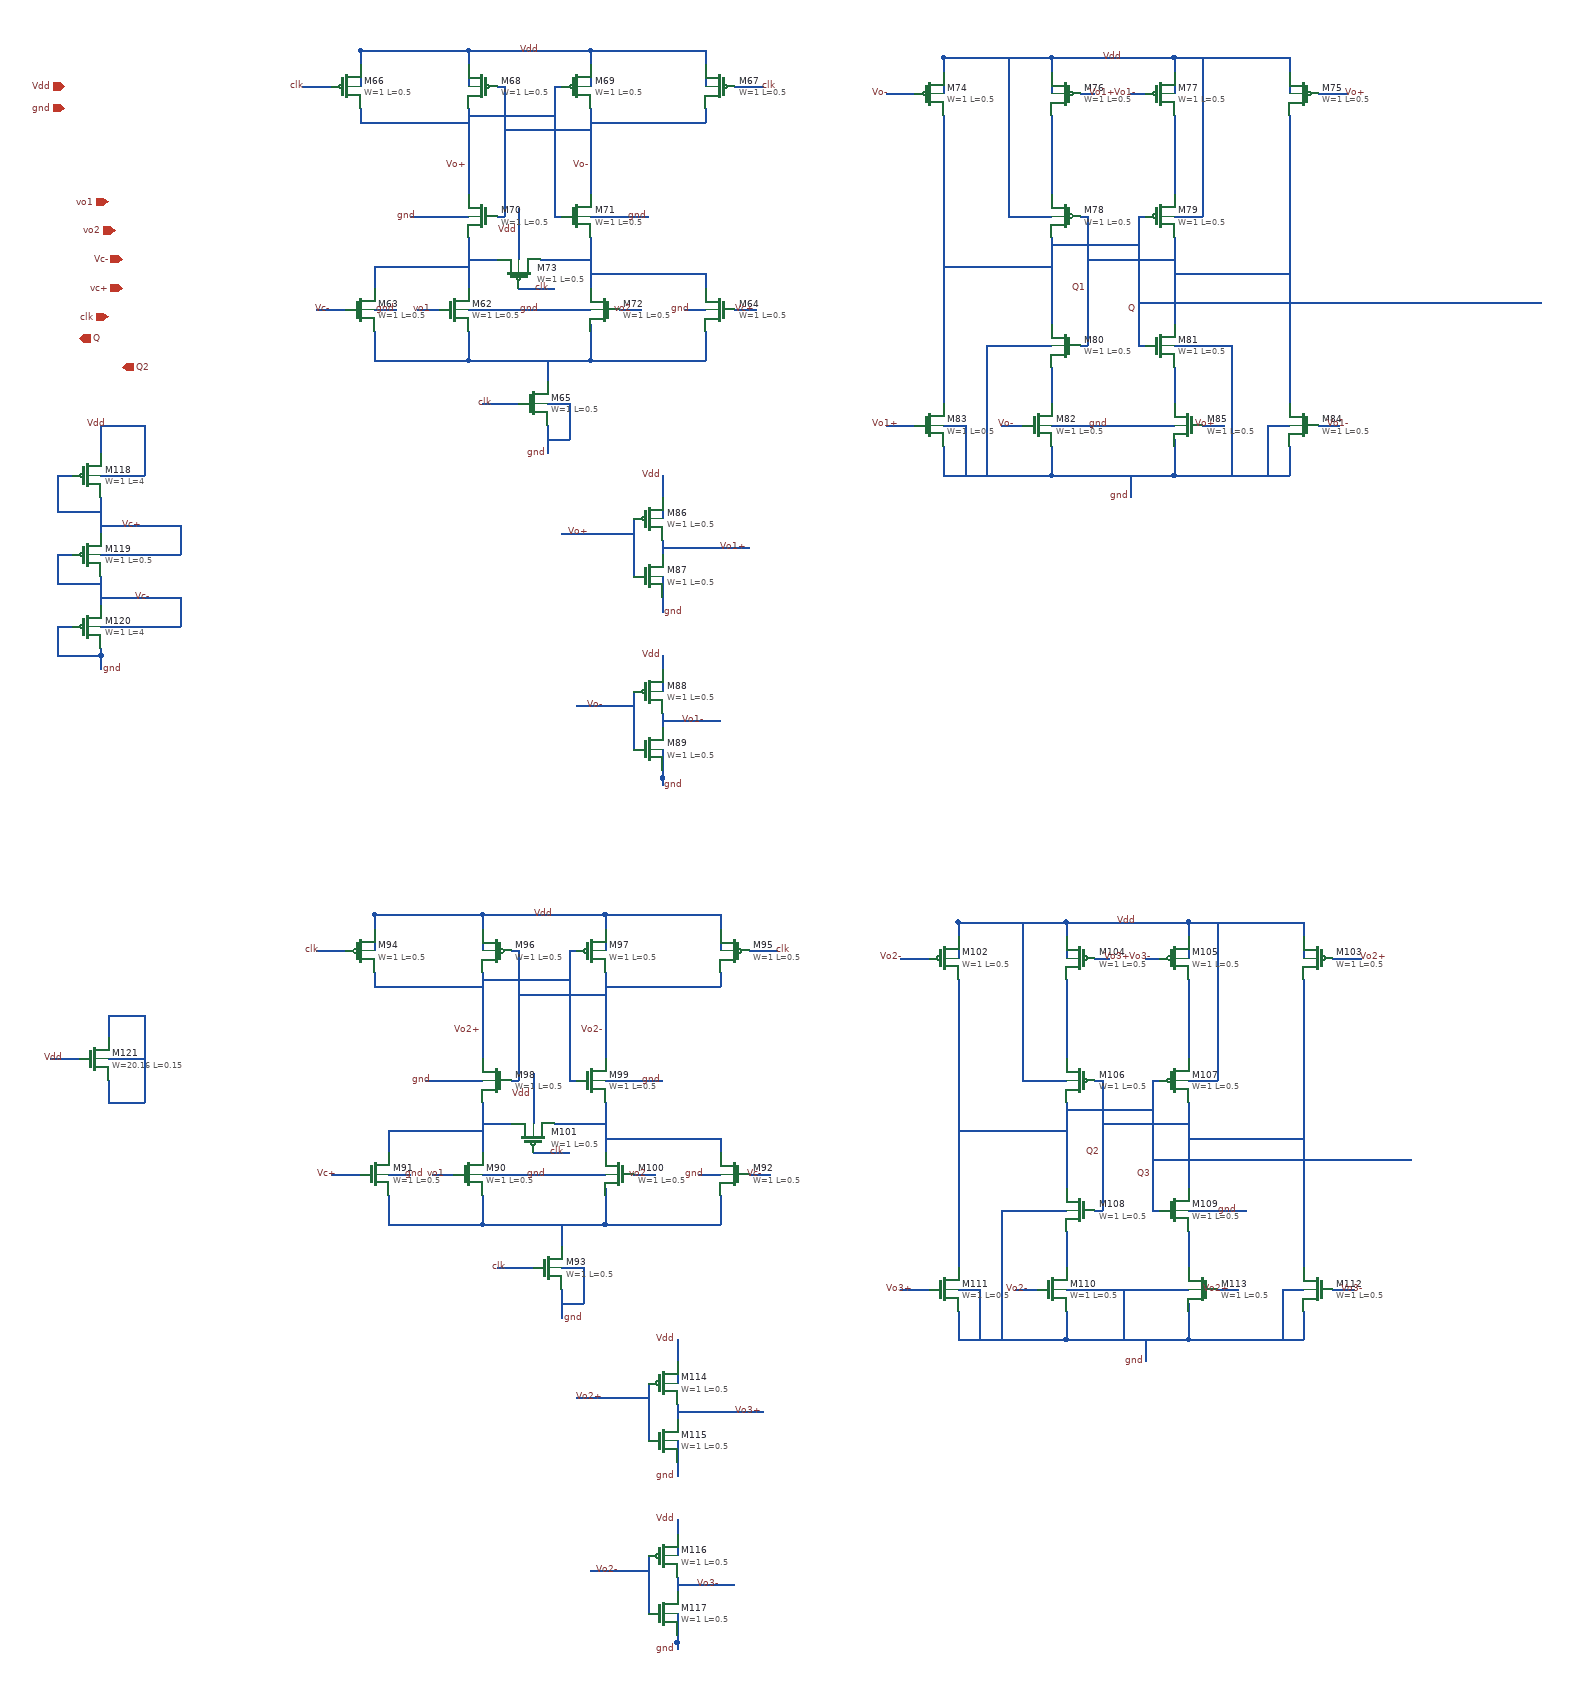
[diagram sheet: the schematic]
v {xschem version=3.4.4 file_version=1.2
}
G {}
K {}
V {}
S {}
E {}
N -830 -240 -830 -120 {
lab=Vo+}
N -660 -240 -660 -130 {
lab=Vo-}
N -660 -130 -660 -120 {
lab=Vo-}
N -830 -320 -830 -300 {
lab=Vdd}
N -830 -320 -660 -320 {
lab=Vdd}
N -660 -320 -660 -300 {
lab=Vdd}
N -790 -270 -780 -270 {
lab=Vo-}
N -780 -270 -780 -90 {
lab=Vo-}
N -790 -90 -780 -90 {
lab=Vo-}
N -710 -270 -700 -270 {
lab=Vo+}
N -710 -270 -710 -90 {
lab=Vo+}
N -710 -90 -700 -90 {
lab=Vo+}
N -980 -320 -830 -320 {
lab=Vdd}
N -980 -320 -980 -300 {
lab=Vdd}
N -660 -320 -500 -320 {
lab=Vdd}
N -500 -320 -500 -300 {
lab=Vdd}
N -980 -240 -980 -220 {
lab=Vo+}
N -980 -220 -830 -220 {
lab=Vo+}
N -500 -240 -500 -220 {
lab=Vo-}
N -660 -220 -500 -220 {
lab=Vo-}
N -830 -230 -710 -230 {
lab=Vo+}
N -780 -210 -660 -210 {
lab=Vo-}
N -830 -60 -830 10 {
lab=#net1}
N -660 -60 -660 10 {
lab=#net2}
N -830 70 -830 110 {
lab=#net3}
N -830 110 -660 110 {
lab=#net3}
N -660 60 -660 110 {
lab=#net3}
N -500 70 -500 110 {
lab=#net3}
N -660 110 -500 110 {
lab=#net3}
N -500 -10 -500 10 {
lab=#net2}
N -660 -10 -500 -10 {
lab=#net2}
N -960 70 -960 110 {
lab=#net3}
N -960 110 -830 110 {
lab=#net3}
N -960 -20 -960 10 {
lab=#net1}
N -960 -20 -830 -20 {
lab=#net1}
N -720 110 -720 140 {
lab=#net3}
N -810 170 -760 170 {
lab=clk}
N -720 200 -720 240 {
lab=gnd}
N -830 -30 -790 -30 {
lab=#net1}
N -730 -30 -660 -30 {
lab=#net2}
N -1040 40 -1000 40 {
lab=Vc-}
N -900 40 -870 40 {
lab=vo1}
N -620 40 -590 40 {
lab=vo2}
N -460 40 -430 40 {
lab=Vc+}
N -460 -270 -420 -270 {
lab=clk}
N -1060 -270 -1020 -270 {
lab=clk}
N -830 40 -660 40 {
lab=gnd}
N -530 40 -500 40 {
lab=gnd}
N -960 40 -930 40 {
lab=gnd}
N -980 -290 -980 -270 {
lab=Vdd}
N -830 -290 -830 -270 {
lab=Vdd}
N -660 -300 -660 -280 {
lab=Vdd}
N -660 -290 -660 -270 {
lab=Vdd}
N -500 -310 -500 -270 {
lab=Vdd}
N -830 -310 -830 -270 {
lab=Vdd}
N -980 -320 -980 -270 {
lab=Vdd}
N -660 -90 -580 -90 {
lab=gnd}
N -910 -90 -830 -90 {
lab=gnd}
N -760 -100 -760 -30 {
lab=Vdd}
N -760 10 -710 10 {
lab=clk}
N -720 170 -690 170 {
lab=gnd}
N -690 170 -690 220 {
lab=gnd}
N -720 220 -690 220 {
lab=gnd}
N -20 -310 -20 -290 {
lab=Vdd}
N -20 -310 150 -310 {
lab=Vdd}
N 150 -310 150 -290 {
lab=Vdd}
N 20 -260 30 -260 {
lab=Vo1+}
N 100 -260 110 -260 {
lab=Vo1-}
N -170 -310 -20 -310 {
lab=Vdd}
N -170 -310 -170 -290 {
lab=Vdd}
N 150 -310 310 -310 {
lab=Vdd}
N 310 -310 310 -290 {
lab=Vdd}
N -170 -230 -170 -210 {
lab=Q}
N 310 -230 310 -210 {
lab=Q1}
N 350 -260 390 -260 {
lab=Vo+}
N -250 -260 -210 -260 {
lab=Vo-}
N -170 -280 -170 -260 {
lab=Vdd}
N -20 -280 -20 -260 {
lab=Vdd}
N 150 -290 150 -270 {
lab=Vdd}
N 150 -280 150 -260 {
lab=Vdd}
N 310 -300 310 -260 {
lab=Vdd}
N -20 -300 -20 -260 {
lab=Vdd}
N -170 -310 -170 -260 {
lab=Vdd}
N 150 -230 150 -140 {
lab=#net4}
N -20 -60 -20 60 {
lab=Q}
N 150 -60 150 50 {
lab=Q1}
N 150 50 150 60 {
lab=Q1}
N -20 -140 -20 -120 {
lab=#net5}
N 150 -140 150 -120 {
lab=#net4}
N 20 -90 30 -90 {
lab=Q1}
N 30 -90 30 90 {
lab=Q1}
N 20 90 30 90 {
lab=Q1}
N 100 -90 110 -90 {
lab=Q}
N 100 -90 100 90 {
lab=Q}
N 100 90 110 90 {
lab=Q}
N -20 -50 100 -50 {
lab=Q}
N 30 -30 150 -30 {
lab=Q1}
N 150 90 230 90 {
lab=gnd}
N -20 -230 -20 -140 {
lab=#net5}
N -20 230 -20 270 {
lab=gnd}
N -20 270 150 270 {
lab=gnd}
N 150 220 150 270 {
lab=gnd}
N 310 230 310 270 {
lab=gnd}
N 150 270 310 270 {
lab=gnd}
N 310 150 310 170 {
lab=Q1}
N -170 230 -170 270 {
lab=gnd}
N -150 270 -20 270 {
lab=gnd}
N -170 140 -170 170 {
lab=Q}
N 90 270 90 300 {
lab=gnd}
N -250 200 -210 200 {
lab=Vo1+}
N -90 200 -60 200 {
lab=Vo-}
N 190 200 220 200 {
lab=Vo+}
N 350 200 380 200 {
lab=Vo1-}
N -20 200 150 200 {
lab=gnd}
N 280 200 310 200 {
lab=gnd}
N -170 200 -140 200 {
lab=gnd}
N -20 120 -20 170 {
lab=#net6}
N 150 120 150 170 {
lab=#net7}
N -170 -210 -170 140 {
lab=Q}
N 310 -210 310 140 {
lab=Q1}
N 310 140 310 150 {
lab=Q1}
N -170 270 -150 270 {
lab=gnd}
N 90 -260 100 -260 {
lab=Vo1-}
N 30 -260 40 -260 {
lab=Vo1+}
N -170 -20 -20 -20 {
lab=Q}
N 150 -10 310 -10 {
lab=Q1}
N -700 350 -620 350 {
lab=Vo+}
N -680 590 -600 590 {
lab=Vo-}
N -560 610 -480 610 {
lab=Vo1-}
N -80 -90 -20 -90 {
lab=Vdd}
N -80 -310 -80 -90 {
lab=Vdd}
N 150 -90 190 -90 {
lab=Vdd}
N 190 -310 190 -90 {
lab=Vdd}
N -110 90 -20 90 {
lab=gnd}
N -110 90 -110 270 {
lab=gnd}
N -560 440 -560 460 {
lab=gnd}
N -600 330 -600 410 {
lab=Vo+}
N -620 350 -600 350 {
lab=Vo+}
N -560 360 -560 380 {
lab=Vo1+}
N -560 370 -440 370 {
lab=Vo1+}
N -560 270 -560 300 {
lab=Vdd}
N -560 280 -560 330 {
lab=Vdd}
N -560 410 -560 450 {
lab=gnd}
N -600 570 -600 650 {
lab=Vo-}
N -560 600 -560 620 {
lab=Vo1-}
N -560 690 -560 700 {
lab=gnd}
N -560 680 -560 690 {
lab=gnd}
N -560 650 -560 690 {
lab=gnd}
N -560 520 -560 540 {
lab=Vdd}
N -560 530 -560 570 {
lab=Vdd}
N -810 960 -810 1080 {
lab=Vo2+}
N -640 960 -640 1070 {
lab=Vo2-}
N -640 1070 -640 1080 {
lab=Vo2-}
N -810 880 -810 900 {
lab=Vdd}
N -810 880 -640 880 {
lab=Vdd}
N -640 880 -640 900 {
lab=Vdd}
N -770 930 -760 930 {
lab=Vo2-}
N -760 930 -760 1110 {
lab=Vo2-}
N -770 1110 -760 1110 {
lab=Vo2-}
N -690 930 -680 930 {
lab=Vo2+}
N -690 930 -690 1110 {
lab=Vo2+}
N -690 1110 -680 1110 {
lab=Vo2+}
N -960 880 -810 880 {
lab=Vdd}
N -960 880 -960 900 {
lab=Vdd}
N -640 880 -480 880 {
lab=Vdd}
N -480 880 -480 900 {
lab=Vdd}
N -960 960 -960 980 {
lab=Vo2+}
N -960 980 -810 980 {
lab=Vo2+}
N -480 960 -480 980 {
lab=Vo2-}
N -640 980 -480 980 {
lab=Vo2-}
N -810 970 -690 970 {
lab=Vo2+}
N -760 990 -640 990 {
lab=Vo2-}
N -810 1140 -810 1210 {
lab=#net8}
N -640 1140 -640 1210 {
lab=#net9}
N -810 1270 -810 1310 {
lab=#net10}
N -810 1310 -640 1310 {
lab=#net10}
N -640 1260 -640 1310 {
lab=#net10}
N -480 1270 -480 1310 {
lab=#net10}
N -640 1310 -480 1310 {
lab=#net10}
N -480 1190 -480 1210 {
lab=#net9}
N -640 1190 -480 1190 {
lab=#net9}
N -940 1270 -940 1310 {
lab=#net10}
N -940 1310 -810 1310 {
lab=#net10}
N -940 1180 -940 1210 {
lab=#net8}
N -940 1180 -810 1180 {
lab=#net8}
N -700 1310 -700 1340 {
lab=#net10}
N -790 1370 -740 1370 {
lab=clk}
N -700 1400 -700 1440 {
lab=#net11}
N -810 1170 -770 1170 {
lab=#net8}
N -710 1170 -640 1170 {
lab=#net9}
N -1020 1240 -980 1240 {
lab=Vc+}
N -880 1240 -850 1240 {
lab=vo1}
N -600 1240 -570 1240 {
lab=vo2}
N -440 1240 -410 1240 {
lab=Vc-}
N -440 930 -400 930 {
lab=clk}
N -1040 930 -1000 930 {
lab=clk}
N -810 1240 -640 1240 {
lab=#net12}
N -510 1240 -480 1240 {
lab=#net13}
N -940 1240 -910 1240 {
lab=#net14}
N -960 910 -960 930 {
lab=Vdd}
N -810 910 -810 930 {
lab=Vdd}
N -640 900 -640 920 {
lab=Vdd}
N -640 910 -640 930 {
lab=Vdd}
N -480 890 -480 930 {
lab=Vdd}
N -810 890 -810 930 {
lab=Vdd}
N -960 880 -960 930 {
lab=Vdd}
N -640 1110 -560 1110 {
lab=GND}
N -890 1110 -810 1110 {
lab=GND}
N -740 1100 -740 1170 {
lab=Vdd}
N -740 1210 -690 1210 {
lab=clk}
N -700 1370 -670 1370 {
lab=#net11}
N -670 1370 -670 1420 {
lab=#net11}
N -700 1420 -670 1420 {
lab=#net11}
N 0 890 0 910 {
lab=Vdd}
N 0 890 170 890 {
lab=Vdd}
N 170 890 170 910 {
lab=Vdd}
N 40 940 50 940 {
lab=Vo3+}
N 120 940 130 940 {
lab=Vo3-}
N -150 890 0 890 {
lab=Vdd}
N -150 890 -150 910 {
lab=Vdd}
N 170 890 330 890 {
lab=Vdd}
N 330 890 330 910 {
lab=Vdd}
N -150 970 -150 990 {
lab=Q3}
N 330 970 330 990 {
lab=Q2}
N 370 940 410 940 {
lab=Vo2+}
N -230 940 -190 940 {
lab=Vo2-}
N -150 920 -150 940 {
lab=Vdd}
N 0 920 0 940 {
lab=Vdd}
N 170 910 170 930 {
lab=Vdd}
N 170 920 170 940 {
lab=Vdd}
N 330 900 330 940 {
lab=Vdd}
N 0 900 0 940 {
lab=Vdd}
N -150 890 -150 940 {
lab=Vdd}
N 170 970 170 1060 {
lab=#net15}
N 0 1140 0 1260 {
lab=Q3}
N 170 1140 170 1250 {
lab=Q2}
N 170 1250 170 1260 {
lab=Q2}
N 0 1060 0 1080 {
lab=#net16}
N 170 1060 170 1080 {
lab=#net15}
N 40 1110 50 1110 {
lab=Q2}
N 50 1110 50 1290 {
lab=Q2}
N 40 1290 50 1290 {
lab=Q2}
N 120 1110 130 1110 {
lab=Q3}
N 120 1110 120 1290 {
lab=Q3}
N 120 1290 130 1290 {
lab=Q3}
N 0 1150 120 1150 {
lab=Q3}
N 50 1170 170 1170 {
lab=Q2}
N 170 1290 250 1290 {
lab=GND}
N 0 970 0 1060 {
lab=#net16}
N 0 1430 0 1470 {
lab=GND}
N 0 1470 170 1470 {
lab=GND}
N 170 1420 170 1470 {
lab=GND}
N 330 1430 330 1470 {
lab=GND}
N 170 1470 330 1470 {
lab=GND}
N 330 1350 330 1370 {
lab=Q2}
N -150 1430 -150 1470 {
lab=GND}
N -130 1470 0 1470 {
lab=GND}
N -150 1340 -150 1370 {
lab=Q3}
N 110 1470 110 1500 {
lab=GND}
N -230 1400 -190 1400 {
lab=Vo3+}
N -70 1400 -40 1400 {
lab=Vo2-}
N 210 1400 240 1400 {
lab=Vo2+}
N 370 1400 400 1400 {
lab=Vo3-}
N 0 1400 170 1400 {
lab=GND}
N 300 1400 330 1400 {
lab=GND}
N -150 1400 -120 1400 {
lab=GND}
N 0 1320 0 1370 {
lab=#net17}
N 170 1320 170 1370 {
lab=#net18}
N -150 990 -150 1340 {
lab=Q3}
N 330 990 330 1340 {
lab=Q2}
N 330 1340 330 1350 {
lab=Q2}
N -150 1470 -130 1470 {
lab=GND}
N 110 940 120 940 {
lab=Vo3-}
N 50 940 60 940 {
lab=Vo3+}
N -150 1180 0 1180 {
lab=Q3}
N 170 1190 330 1190 {
lab=Q2}
N -680 1550 -600 1550 {
lab=Vo2+}
N -660 1790 -580 1790 {
lab=Vo2-}
N -540 1810 -460 1810 {
lab=Vo3-}
N -60 1110 0 1110 {
lab=Vdd}
N -60 890 -60 1110 {
lab=Vdd}
N 170 1110 210 1110 {
lab=Vdd}
N 210 890 210 1110 {
lab=Vdd}
N -90 1290 0 1290 {
lab=GND}
N -90 1290 -90 1470 {
lab=GND}
N -540 1640 -540 1660 {
lab=#net19}
N -580 1530 -580 1610 {
lab=Vo2+}
N -600 1550 -580 1550 {
lab=Vo2+}
N -540 1560 -540 1580 {
lab=Vo3+}
N -540 1570 -420 1570 {
lab=Vo3+}
N -540 1470 -540 1500 {
lab=Vdd}
N -540 1480 -540 1530 {
lab=Vdd}
N -540 1610 -540 1650 {
lab=#net19}
N -580 1770 -580 1850 {
lab=Vo2-}
N -540 1800 -540 1820 {
lab=Vo3-}
N -540 1890 -540 1900 {
lab=#net20}
N -540 1880 -540 1890 {
lab=#net20}
N -540 1850 -540 1890 {
lab=#net20}
N -540 1720 -540 1740 {
lab=Vdd}
N -540 1730 -540 1770 {
lab=Vdd}
N 100 30 660 30 {
lab=Q}
N 120 1220 480 1220 {
lab=Q3}
N -1340 410 -1340 450 {
lab=Vc-}
N -1340 330 -1340 350 {
lab=Vc+}
N -1340 380 -1320 380 {
lab=Vc+}
N -1340 340 -1320 340 {
lab=Vc+}
N -1340 480 -1310 480 {
lab=Vc-}
N -1340 440 -1310 440 {
lab=Vc-}
N -1400 380 -1380 380 {
lab=Vc-}
N -1400 480 -1380 480 {
lab=gnd}
N -1400 380 -1400 420 {
lab=Vc-}
N -1400 420 -1340 420 {
lab=Vc-}
N -1400 480 -1400 520 {
lab=gnd}
N -1400 520 -1340 520 {
lab=gnd}
N -1340 300 -1340 330 {
lab=Vc+}
N -1310 480 -1230 480 {
lab=Vc-}
N -1320 380 -1230 380 {
lab=Vc+}
N -1230 340 -1230 380 {
lab=Vc+}
N -1320 340 -1230 340 {
lab=Vc+}
N -1230 440 -1230 480 {
lab=Vc-}
N -1340 210 -1340 240 {
lab=Vdd}
N -1400 270 -1380 270 {
lab=Vc+}
N -1400 270 -1400 320 {
lab=Vc+}
N -1400 320 -1340 320 {
lab=Vc+}
N -1340 270 -1280 270 {
lab=Vdd}
N -1280 230 -1280 270 {
lab=Vdd}
N -1340 520 -1340 540 {
lab=gnd}
N -1280 200 -1280 230 {
lab=Vdd}
N -1340 200 -1280 200 {
lab=Vdd}
N -1340 200 -1340 210 {
lab=Vdd}
N -1340 510 -1340 520 {
lab=gnd}
N -1310 440 -1230 440 {
lab=Vc-}
N -1410 1080 -1370 1080 {
lab=Vdd}
N -1330 1020 -1330 1050 {
lab=#net21}
N -1330 1020 -1280 1020 {
lab=#net21}
N -1280 1020 -1280 1140 {
lab=#net21}
N -1330 1140 -1280 1140 {
lab=#net21}
N -1330 1110 -1330 1140 {
lab=#net21}
N -1330 1080 -1280 1080 {
lab=#net21}
N -140 200 -140 270 {
lab=gnd}
N 280 200 280 270 {
lab=gnd}
N 230 90 230 270 {
lab=gnd}
N -120 1400 -120 1470 {}
N 80 1400 80 1470 {}
N 300 1400 300 1470 {}
C {sky130_fd_pr/nfet_01v8.sym} -850 40 0 0 {name=M62
L=0.5
W=1
nf=1 
mult=1
ad="'int((nf+1)/2) * W/nf * 0.29'" 
pd="'2*int((nf+1)/2) * (W/nf + 0.29)'"
as="'int((nf+2)/2) * W/nf * 0.29'" 
ps="'2*int((nf+2)/2) * (W/nf + 0.29)'"
nrd="'0.29 / W'" nrs="'0.29 / W'"
sa=0 sb=0 sd=0
model=nfet_01v8
spiceprefix=X
}
C {sky130_fd_pr/nfet_01v8.sym} -980 40 0 0 {name=M63
L=0.5
W=1
nf=1 
mult=1
ad="'int((nf+1)/2) * W/nf * 0.29'" 
pd="'2*int((nf+1)/2) * (W/nf + 0.29)'"
as="'int((nf+2)/2) * W/nf * 0.29'" 
ps="'2*int((nf+2)/2) * (W/nf + 0.29)'"
nrd="'0.29 / W'" nrs="'0.29 / W'"
sa=0 sb=0 sd=0
model=nfet_01v8
spiceprefix=X
}
C {sky130_fd_pr/nfet_01v8.sym} -480 40 0 1 {name=M64
L=0.5
W=1
nf=1 
mult=1
ad="'int((nf+1)/2) * W/nf * 0.29'" 
pd="'2*int((nf+1)/2) * (W/nf + 0.29)'"
as="'int((nf+2)/2) * W/nf * 0.29'" 
ps="'2*int((nf+2)/2) * (W/nf + 0.29)'"
nrd="'0.29 / W'" nrs="'0.29 / W'"
sa=0 sb=0 sd=0
model=nfet_01v8
spiceprefix=X
}
C {sky130_fd_pr/nfet_01v8.sym} -740 170 0 0 {name=M65
L=0.5
W=1
nf=1 
mult=1
ad="'int((nf+1)/2) * W/nf * 0.29'" 
pd="'2*int((nf+1)/2) * (W/nf + 0.29)'"
as="'int((nf+2)/2) * W/nf * 0.29'" 
ps="'2*int((nf+2)/2) * (W/nf + 0.29)'"
nrd="'0.29 / W'" nrs="'0.29 / W'"
sa=0 sb=0 sd=0
model=nfet_01v8
spiceprefix=X
}
C {sky130_fd_pr/pfet_01v8.sym} -1000 -270 0 0 {name=M66
L=0.5
W=1
nf=1
mult=1
ad="'int((nf+1)/2) * W/nf * 0.29'" 
pd="'2*int((nf+1)/2) * (W/nf + 0.29)'"
as="'int((nf+2)/2) * W/nf * 0.29'" 
ps="'2*int((nf+2)/2) * (W/nf + 0.29)'"
nrd="'0.29 / W'" nrs="'0.29 / W'"
sa=0 sb=0 sd=0
model=pfet_01v8
spiceprefix=X
}
C {sky130_fd_pr/pfet_01v8.sym} -480 -270 0 1 {name=M67
L=0.5
W=1
nf=1
mult=1
ad="'int((nf+1)/2) * W/nf * 0.29'" 
pd="'2*int((nf+1)/2) * (W/nf + 0.29)'"
as="'int((nf+2)/2) * W/nf * 0.29'" 
ps="'2*int((nf+2)/2) * (W/nf + 0.29)'"
nrd="'0.29 / W'" nrs="'0.29 / W'"
sa=0 sb=0 sd=0
model=pfet_01v8
spiceprefix=X
}
C {sky130_fd_pr/pfet_01v8.sym} -810 -270 0 1 {name=M68
L=0.5
W=1
nf=1
mult=1
ad="'int((nf+1)/2) * W/nf * 0.29'" 
pd="'2*int((nf+1)/2) * (W/nf + 0.29)'"
as="'int((nf+2)/2) * W/nf * 0.29'" 
ps="'2*int((nf+2)/2) * (W/nf + 0.29)'"
nrd="'0.29 / W'" nrs="'0.29 / W'"
sa=0 sb=0 sd=0
model=pfet_01v8
spiceprefix=X
}
C {sky130_fd_pr/pfet_01v8.sym} -680 -270 0 0 {name=M69
L=0.5
W=1
nf=1
mult=1
ad="'int((nf+1)/2) * W/nf * 0.29'" 
pd="'2*int((nf+1)/2) * (W/nf + 0.29)'"
as="'int((nf+2)/2) * W/nf * 0.29'" 
ps="'2*int((nf+2)/2) * (W/nf + 0.29)'"
nrd="'0.29 / W'" nrs="'0.29 / W'"
sa=0 sb=0 sd=0
model=pfet_01v8
spiceprefix=X
}
C {sky130_fd_pr/nfet_01v8.sym} -810 -90 0 1 {name=M70
L=0.5
W=1
nf=1 
mult=1
ad="'int((nf+1)/2) * W/nf * 0.29'" 
pd="'2*int((nf+1)/2) * (W/nf + 0.29)'"
as="'int((nf+2)/2) * W/nf * 0.29'" 
ps="'2*int((nf+2)/2) * (W/nf + 0.29)'"
nrd="'0.29 / W'" nrs="'0.29 / W'"
sa=0 sb=0 sd=0
model=nfet_01v8
spiceprefix=X
}
C {sky130_fd_pr/nfet_01v8.sym} -680 -90 0 0 {name=M71
L=0.5
W=1
nf=1 
mult=1
ad="'int((nf+1)/2) * W/nf * 0.29'" 
pd="'2*int((nf+1)/2) * (W/nf + 0.29)'"
as="'int((nf+2)/2) * W/nf * 0.29'" 
ps="'2*int((nf+2)/2) * (W/nf + 0.29)'"
nrd="'0.29 / W'" nrs="'0.29 / W'"
sa=0 sb=0 sd=0
model=nfet_01v8
spiceprefix=X
}
C {sky130_fd_pr/nfet_01v8.sym} -640 40 0 1 {name=M72
L=0.5
W=1
nf=1 
mult=1
ad="'int((nf+1)/2) * W/nf * 0.29'" 
pd="'2*int((nf+1)/2) * (W/nf + 0.29)'"
as="'int((nf+2)/2) * W/nf * 0.29'" 
ps="'2*int((nf+2)/2) * (W/nf + 0.29)'"
nrd="'0.29 / W'" nrs="'0.29 / W'"
sa=0 sb=0 sd=0
model=nfet_01v8
spiceprefix=X
}
C {devices/lab_wire.sym} -730 -320 0 0 {name=p75 sig_type=std_logic lab=Vdd
}
C {sky130_fd_pr/pfet_01v8.sym} -760 -10 1 1 {name=M73
L=0.5
W=1
nf=1
mult=1
ad="'int((nf+1)/2) * W/nf * 0.29'" 
pd="'2*int((nf+1)/2) * (W/nf + 0.29)'"
as="'int((nf+2)/2) * W/nf * 0.29'" 
ps="'2*int((nf+2)/2) * (W/nf + 0.29)'"
nrd="'0.29 / W'" nrs="'0.29 / W'"
sa=0 sb=0 sd=0
model=pfet_01v8
spiceprefix=X
}
C {devices/lab_wire.sym} -760 -70 1 0 {name=p76 sig_type=std_logic lab=Vdd
}
C {devices/lab_wire.sym} -430 40 0 0 {name=p77 sig_type=std_logic lab=Vc+
}
C {devices/lab_wire.sym} -1020 40 0 0 {name=p78 sig_type=std_logic lab=Vc-
}
C {devices/lab_wire.sym} -880 40 0 0 {name=p79 sig_type=std_logic lab=vo1
}
C {devices/lab_wire.sym} -600 40 0 0 {name=p80 sig_type=std_logic lab=vo2
}
C {devices/lab_pin.sym} -795 170 0 0 {name=p81 sig_type=std_logic lab=clk
}
C {devices/lab_pin.sym} -715 10 0 0 {name=p82 sig_type=std_logic lab=clk
}
C {devices/lab_pin.sym} -1055 -270 0 0 {name=p83 sig_type=std_logic lab=clk
}
C {devices/lab_pin.sym} -425 -270 0 1 {name=p84 sig_type=std_logic lab=clk
}
C {devices/lab_wire.sym} -830 -160 0 0 {name=p85 sig_type=std_logic lab=Vo+
}
C {devices/lab_wire.sym} -660 -160 0 0 {name=p86 sig_type=std_logic lab=Vo-
}
C {sky130_fd_pr/pfet_01v8.sym} -190 -260 0 0 {name=M74
L=0.5
W=1
nf=1
mult=1
ad="'int((nf+1)/2) * W/nf * 0.29'" 
pd="'2*int((nf+1)/2) * (W/nf + 0.29)'"
as="'int((nf+2)/2) * W/nf * 0.29'" 
ps="'2*int((nf+2)/2) * (W/nf + 0.29)'"
nrd="'0.29 / W'" nrs="'0.29 / W'"
sa=0 sb=0 sd=0
model=pfet_01v8
spiceprefix=X
}
C {sky130_fd_pr/pfet_01v8.sym} 330 -260 0 1 {name=M75
L=0.5
W=1
nf=1
mult=1
ad="'int((nf+1)/2) * W/nf * 0.29'" 
pd="'2*int((nf+1)/2) * (W/nf + 0.29)'"
as="'int((nf+2)/2) * W/nf * 0.29'" 
ps="'2*int((nf+2)/2) * (W/nf + 0.29)'"
nrd="'0.29 / W'" nrs="'0.29 / W'"
sa=0 sb=0 sd=0
model=pfet_01v8
spiceprefix=X
}
C {sky130_fd_pr/pfet_01v8.sym} 0 -260 0 1 {name=M76
L=0.5
W=1
nf=1
mult=1
ad="'int((nf+1)/2) * W/nf * 0.29'" 
pd="'2*int((nf+1)/2) * (W/nf + 0.29)'"
as="'int((nf+2)/2) * W/nf * 0.29'" 
ps="'2*int((nf+2)/2) * (W/nf + 0.29)'"
nrd="'0.29 / W'" nrs="'0.29 / W'"
sa=0 sb=0 sd=0
model=pfet_01v8
spiceprefix=X
}
C {sky130_fd_pr/pfet_01v8.sym} 130 -260 0 0 {name=M77
L=0.5
W=1
nf=1
mult=1
ad="'int((nf+1)/2) * W/nf * 0.29'" 
pd="'2*int((nf+1)/2) * (W/nf + 0.29)'"
as="'int((nf+2)/2) * W/nf * 0.29'" 
ps="'2*int((nf+2)/2) * (W/nf + 0.29)'"
nrd="'0.29 / W'" nrs="'0.29 / W'"
sa=0 sb=0 sd=0
model=pfet_01v8
spiceprefix=X
}
C {devices/lab_wire.sym} 80 -310 0 0 {name=p87 sig_type=std_logic lab=Vdd
}
C {devices/lab_pin.sym} -245 -260 0 0 {name=p88 sig_type=std_logic lab=Vo-
}
C {devices/lab_pin.sym} 385 -260 0 1 {name=p89 sig_type=std_logic lab=Vo+
}
C {sky130_fd_pr/pfet_01v8.sym} 0 -90 0 1 {name=M78
L=0.5
W=1
nf=1
mult=1
ad="'int((nf+1)/2) * W/nf * 0.29'" 
pd="'2*int((nf+1)/2) * (W/nf + 0.29)'"
as="'int((nf+2)/2) * W/nf * 0.29'" 
ps="'2*int((nf+2)/2) * (W/nf + 0.29)'"
nrd="'0.29 / W'" nrs="'0.29 / W'"
sa=0 sb=0 sd=0
model=pfet_01v8
spiceprefix=X
}
C {sky130_fd_pr/pfet_01v8.sym} 130 -90 0 0 {name=M79
L=0.5
W=1
nf=1
mult=1
ad="'int((nf+1)/2) * W/nf * 0.29'" 
pd="'2*int((nf+1)/2) * (W/nf + 0.29)'"
as="'int((nf+2)/2) * W/nf * 0.29'" 
ps="'2*int((nf+2)/2) * (W/nf + 0.29)'"
nrd="'0.29 / W'" nrs="'0.29 / W'"
sa=0 sb=0 sd=0
model=pfet_01v8
spiceprefix=X
}
C {sky130_fd_pr/nfet_01v8.sym} 0 90 0 1 {name=M80
L=0.5
W=1
nf=1 
mult=1
ad="'int((nf+1)/2) * W/nf * 0.29'" 
pd="'2*int((nf+1)/2) * (W/nf + 0.29)'"
as="'int((nf+2)/2) * W/nf * 0.29'" 
ps="'2*int((nf+2)/2) * (W/nf + 0.29)'"
nrd="'0.29 / W'" nrs="'0.29 / W'"
sa=0 sb=0 sd=0
model=nfet_01v8
spiceprefix=X
}
C {sky130_fd_pr/nfet_01v8.sym} 130 90 0 0 {name=M81
L=0.5
W=1
nf=1 
mult=1
ad="'int((nf+1)/2) * W/nf * 0.29'" 
pd="'2*int((nf+1)/2) * (W/nf + 0.29)'"
as="'int((nf+2)/2) * W/nf * 0.29'" 
ps="'2*int((nf+2)/2) * (W/nf + 0.29)'"
nrd="'0.29 / W'" nrs="'0.29 / W'"
sa=0 sb=0 sd=0
model=nfet_01v8
spiceprefix=X
}
C {sky130_fd_pr/nfet_01v8.sym} -40 200 0 0 {name=M82
L=0.5
W=1
nf=1 
mult=1
ad="'int((nf+1)/2) * W/nf * 0.29'" 
pd="'2*int((nf+1)/2) * (W/nf + 0.29)'"
as="'int((nf+2)/2) * W/nf * 0.29'" 
ps="'2*int((nf+2)/2) * (W/nf + 0.29)'"
nrd="'0.29 / W'" nrs="'0.29 / W'"
sa=0 sb=0 sd=0
model=nfet_01v8
spiceprefix=X
}
C {sky130_fd_pr/nfet_01v8.sym} -190 200 0 0 {name=M83
L=0.5
W=1
nf=1 
mult=1
ad="'int((nf+1)/2) * W/nf * 0.29'" 
pd="'2*int((nf+1)/2) * (W/nf + 0.29)'"
as="'int((nf+2)/2) * W/nf * 0.29'" 
ps="'2*int((nf+2)/2) * (W/nf + 0.29)'"
nrd="'0.29 / W'" nrs="'0.29 / W'"
sa=0 sb=0 sd=0
model=nfet_01v8
spiceprefix=X
}
C {sky130_fd_pr/nfet_01v8.sym} 330 200 0 1 {name=M84
L=0.5
W=1
nf=1 
mult=1
ad="'int((nf+1)/2) * W/nf * 0.29'" 
pd="'2*int((nf+1)/2) * (W/nf + 0.29)'"
as="'int((nf+2)/2) * W/nf * 0.29'" 
ps="'2*int((nf+2)/2) * (W/nf + 0.29)'"
nrd="'0.29 / W'" nrs="'0.29 / W'"
sa=0 sb=0 sd=0
model=nfet_01v8
spiceprefix=X
}
C {sky130_fd_pr/nfet_01v8.sym} 170 200 0 1 {name=M85
L=0.5
W=1
nf=1 
mult=1
ad="'int((nf+1)/2) * W/nf * 0.29'" 
pd="'2*int((nf+1)/2) * (W/nf + 0.29)'"
as="'int((nf+2)/2) * W/nf * 0.29'" 
ps="'2*int((nf+2)/2) * (W/nf + 0.29)'"
nrd="'0.29 / W'" nrs="'0.29 / W'"
sa=0 sb=0 sd=0
model=nfet_01v8
spiceprefix=X
}
C {devices/lab_wire.sym} -70 200 0 0 {name=p90 sig_type=std_logic lab=Vo-
}
C {devices/lab_wire.sym} 210 200 0 0 {name=p91 sig_type=std_logic lab=Vo+

}
C {devices/lab_wire.sym} -660 350 0 0 {name=p92 sig_type=std_logic lab=Vo+
}
C {devices/lab_wire.sym} -640 590 0 0 {name=p93 sig_type=std_logic lab=Vo-
}
C {devices/lab_wire.sym} -440 370 0 0 {name=p94 sig_type=std_logic lab=Vo1+
}
C {devices/lab_wire.sym} -500 610 0 0 {name=p95 sig_type=std_logic lab=Vo1-
}
C {devices/lab_wire.sym} 30 -260 0 1 {name=p96 sig_type=std_logic lab=Vo1+
}
C {devices/lab_wire.sym} 100 -260 0 0 {name=p97 sig_type=std_logic lab=Vo1-
}
C {devices/lab_wire.sym} -230 200 0 0 {name=p98 sig_type=std_logic lab=Vo1+
}
C {devices/lab_wire.sym} 360 200 0 1 {name=p99 sig_type=std_logic lab=Vo1-
}
C {devices/lab_wire.sym} 30 10 0 0 {name=p100 sig_type=std_logic lab=Q1
}
C {devices/lab_wire.sym} 100 40 0 0 {name=p101 sig_type=std_logic lab=Q
}
C {devices/lab_wire.sym} -560 270 0 0 {name=p102 sig_type=std_logic lab=Vdd
}
C {sky130_fd_pr/pfet_01v8.sym} -580 330 0 0 {name=M86
L=0.5
W=1
nf=1
mult=1
ad="'int((nf+1)/2) * W/nf * 0.29'" 
pd="'2*int((nf+1)/2) * (W/nf + 0.29)'"
as="'int((nf+2)/2) * W/nf * 0.29'" 
ps="'2*int((nf+2)/2) * (W/nf + 0.29)'"
nrd="'0.29 / W'" nrs="'0.29 / W'"
sa=0 sb=0 sd=0
model=pfet_01v8
spiceprefix=X
}
C {sky130_fd_pr/nfet_01v8.sym} -580 410 0 0 {name=M87
L=0.5
W=1
nf=1 
mult=1
ad="'int((nf+1)/2) * W/nf * 0.29'" 
pd="'2*int((nf+1)/2) * (W/nf + 0.29)'"
as="'int((nf+2)/2) * W/nf * 0.29'" 
ps="'2*int((nf+2)/2) * (W/nf + 0.29)'"
nrd="'0.29 / W'" nrs="'0.29 / W'"
sa=0 sb=0 sd=0
model=nfet_01v8
spiceprefix=X
}
C {sky130_fd_pr/pfet_01v8.sym} -580 570 0 0 {name=M88
L=0.5
W=1
nf=1
mult=1
ad="'int((nf+1)/2) * W/nf * 0.29'" 
pd="'2*int((nf+1)/2) * (W/nf + 0.29)'"
as="'int((nf+2)/2) * W/nf * 0.29'" 
ps="'2*int((nf+2)/2) * (W/nf + 0.29)'"
nrd="'0.29 / W'" nrs="'0.29 / W'"
sa=0 sb=0 sd=0
model=pfet_01v8
spiceprefix=X
}
C {sky130_fd_pr/nfet_01v8.sym} -580 650 0 0 {name=M89
L=0.5
W=1
nf=1 
mult=1
ad="'int((nf+1)/2) * W/nf * 0.29'" 
pd="'2*int((nf+1)/2) * (W/nf + 0.29)'"
as="'int((nf+2)/2) * W/nf * 0.29'" 
ps="'2*int((nf+2)/2) * (W/nf + 0.29)'"
nrd="'0.29 / W'" nrs="'0.29 / W'"
sa=0 sb=0 sd=0
model=nfet_01v8
spiceprefix=X
}
C {devices/lab_wire.sym} -560 520 0 0 {name=p103 sig_type=std_logic lab=Vdd
}
C {sky130_fd_pr/nfet_01v8.sym} -830 1240 0 0 {name=M90
L=0.5
W=1
nf=1 
mult=1
ad="'int((nf+1)/2) * W/nf * 0.29'" 
pd="'2*int((nf+1)/2) * (W/nf + 0.29)'"
as="'int((nf+2)/2) * W/nf * 0.29'" 
ps="'2*int((nf+2)/2) * (W/nf + 0.29)'"
nrd="'0.29 / W'" nrs="'0.29 / W'"
sa=0 sb=0 sd=0
model=nfet_01v8
spiceprefix=X
}
C {sky130_fd_pr/nfet_01v8.sym} -960 1240 0 0 {name=M91
L=0.5
W=1
nf=1 
mult=1
ad="'int((nf+1)/2) * W/nf * 0.29'" 
pd="'2*int((nf+1)/2) * (W/nf + 0.29)'"
as="'int((nf+2)/2) * W/nf * 0.29'" 
ps="'2*int((nf+2)/2) * (W/nf + 0.29)'"
nrd="'0.29 / W'" nrs="'0.29 / W'"
sa=0 sb=0 sd=0
model=nfet_01v8
spiceprefix=X
}
C {sky130_fd_pr/nfet_01v8.sym} -460 1240 0 1 {name=M92
L=0.5
W=1
nf=1 
mult=1
ad="'int((nf+1)/2) * W/nf * 0.29'" 
pd="'2*int((nf+1)/2) * (W/nf + 0.29)'"
as="'int((nf+2)/2) * W/nf * 0.29'" 
ps="'2*int((nf+2)/2) * (W/nf + 0.29)'"
nrd="'0.29 / W'" nrs="'0.29 / W'"
sa=0 sb=0 sd=0
model=nfet_01v8
spiceprefix=X
}
C {sky130_fd_pr/nfet_01v8.sym} -720 1370 0 0 {name=M93
L=0.5
W=1
nf=1 
mult=1
ad="'int((nf+1)/2) * W/nf * 0.29'" 
pd="'2*int((nf+1)/2) * (W/nf + 0.29)'"
as="'int((nf+2)/2) * W/nf * 0.29'" 
ps="'2*int((nf+2)/2) * (W/nf + 0.29)'"
nrd="'0.29 / W'" nrs="'0.29 / W'"
sa=0 sb=0 sd=0
model=nfet_01v8
spiceprefix=X
}
C {sky130_fd_pr/pfet_01v8.sym} -980 930 0 0 {name=M94
L=0.5
W=1
nf=1
mult=1
ad="'int((nf+1)/2) * W/nf * 0.29'" 
pd="'2*int((nf+1)/2) * (W/nf + 0.29)'"
as="'int((nf+2)/2) * W/nf * 0.29'" 
ps="'2*int((nf+2)/2) * (W/nf + 0.29)'"
nrd="'0.29 / W'" nrs="'0.29 / W'"
sa=0 sb=0 sd=0
model=pfet_01v8
spiceprefix=X
}
C {sky130_fd_pr/pfet_01v8.sym} -460 930 0 1 {name=M95
L=0.5
W=1
nf=1
mult=1
ad="'int((nf+1)/2) * W/nf * 0.29'" 
pd="'2*int((nf+1)/2) * (W/nf + 0.29)'"
as="'int((nf+2)/2) * W/nf * 0.29'" 
ps="'2*int((nf+2)/2) * (W/nf + 0.29)'"
nrd="'0.29 / W'" nrs="'0.29 / W'"
sa=0 sb=0 sd=0
model=pfet_01v8
spiceprefix=X
}
C {sky130_fd_pr/pfet_01v8.sym} -790 930 0 1 {name=M96
L=0.5
W=1
nf=1
mult=1
ad="'int((nf+1)/2) * W/nf * 0.29'" 
pd="'2*int((nf+1)/2) * (W/nf + 0.29)'"
as="'int((nf+2)/2) * W/nf * 0.29'" 
ps="'2*int((nf+2)/2) * (W/nf + 0.29)'"
nrd="'0.29 / W'" nrs="'0.29 / W'"
sa=0 sb=0 sd=0
model=pfet_01v8
spiceprefix=X
}
C {sky130_fd_pr/pfet_01v8.sym} -660 930 0 0 {name=M97
L=0.5
W=1
nf=1
mult=1
ad="'int((nf+1)/2) * W/nf * 0.29'" 
pd="'2*int((nf+1)/2) * (W/nf + 0.29)'"
as="'int((nf+2)/2) * W/nf * 0.29'" 
ps="'2*int((nf+2)/2) * (W/nf + 0.29)'"
nrd="'0.29 / W'" nrs="'0.29 / W'"
sa=0 sb=0 sd=0
model=pfet_01v8
spiceprefix=X
}
C {sky130_fd_pr/nfet_01v8.sym} -790 1110 0 1 {name=M98
L=0.5
W=1
nf=1 
mult=1
ad="'int((nf+1)/2) * W/nf * 0.29'" 
pd="'2*int((nf+1)/2) * (W/nf + 0.29)'"
as="'int((nf+2)/2) * W/nf * 0.29'" 
ps="'2*int((nf+2)/2) * (W/nf + 0.29)'"
nrd="'0.29 / W'" nrs="'0.29 / W'"
sa=0 sb=0 sd=0
model=nfet_01v8
spiceprefix=X
}
C {sky130_fd_pr/nfet_01v8.sym} -660 1110 0 0 {name=M99
L=0.5
W=1
nf=1 
mult=1
ad="'int((nf+1)/2) * W/nf * 0.29'" 
pd="'2*int((nf+1)/2) * (W/nf + 0.29)'"
as="'int((nf+2)/2) * W/nf * 0.29'" 
ps="'2*int((nf+2)/2) * (W/nf + 0.29)'"
nrd="'0.29 / W'" nrs="'0.29 / W'"
sa=0 sb=0 sd=0
model=nfet_01v8
spiceprefix=X
}
C {sky130_fd_pr/nfet_01v8.sym} -620 1240 0 1 {name=M100
L=0.5
W=1
nf=1 
mult=1
ad="'int((nf+1)/2) * W/nf * 0.29'" 
pd="'2*int((nf+1)/2) * (W/nf + 0.29)'"
as="'int((nf+2)/2) * W/nf * 0.29'" 
ps="'2*int((nf+2)/2) * (W/nf + 0.29)'"
nrd="'0.29 / W'" nrs="'0.29 / W'"
sa=0 sb=0 sd=0
model=nfet_01v8
spiceprefix=X
}
C {devices/lab_wire.sym} -710 880 0 0 {name=p104 sig_type=std_logic lab=Vdd
}
C {sky130_fd_pr/pfet_01v8.sym} -740 1190 1 1 {name=M101
L=0.5
W=1
nf=1
mult=1
ad="'int((nf+1)/2) * W/nf * 0.29'" 
pd="'2*int((nf+1)/2) * (W/nf + 0.29)'"
as="'int((nf+2)/2) * W/nf * 0.29'" 
ps="'2*int((nf+2)/2) * (W/nf + 0.29)'"
nrd="'0.29 / W'" nrs="'0.29 / W'"
sa=0 sb=0 sd=0
model=pfet_01v8
spiceprefix=X
}
C {devices/lab_wire.sym} -740 1130 1 0 {name=p105 sig_type=std_logic lab=Vdd
}
C {devices/lab_wire.sym} -860 1240 0 0 {name=p106 sig_type=std_logic lab=vo1
}
C {devices/lab_wire.sym} -580 1240 0 0 {name=p107 sig_type=std_logic lab=vo2
}
C {devices/lab_pin.sym} -775 1370 0 0 {name=p108 sig_type=std_logic lab=clk
}
C {devices/lab_pin.sym} -695 1210 0 0 {name=p109 sig_type=std_logic lab=clk
}
C {devices/lab_pin.sym} -1035 930 0 0 {name=p110 sig_type=std_logic lab=clk
}
C {devices/lab_pin.sym} -405 930 0 1 {name=p111 sig_type=std_logic lab=clk
}
C {devices/lab_wire.sym} -810 1040 0 0 {name=p112 sig_type=std_logic lab=Vo2+
}
C {devices/lab_wire.sym} -640 1040 0 0 {name=p113 sig_type=std_logic lab=Vo2-
}
C {sky130_fd_pr/pfet_01v8.sym} -170 940 0 0 {name=M102
L=0.5
W=1
nf=1
mult=1
ad="'int((nf+1)/2) * W/nf * 0.29'" 
pd="'2*int((nf+1)/2) * (W/nf + 0.29)'"
as="'int((nf+2)/2) * W/nf * 0.29'" 
ps="'2*int((nf+2)/2) * (W/nf + 0.29)'"
nrd="'0.29 / W'" nrs="'0.29 / W'"
sa=0 sb=0 sd=0
model=pfet_01v8
spiceprefix=X
}
C {sky130_fd_pr/pfet_01v8.sym} 350 940 0 1 {name=M103
L=0.5
W=1
nf=1
mult=1
ad="'int((nf+1)/2) * W/nf * 0.29'" 
pd="'2*int((nf+1)/2) * (W/nf + 0.29)'"
as="'int((nf+2)/2) * W/nf * 0.29'" 
ps="'2*int((nf+2)/2) * (W/nf + 0.29)'"
nrd="'0.29 / W'" nrs="'0.29 / W'"
sa=0 sb=0 sd=0
model=pfet_01v8
spiceprefix=X
}
C {sky130_fd_pr/pfet_01v8.sym} 20 940 0 1 {name=M104
L=0.5
W=1
nf=1
mult=1
ad="'int((nf+1)/2) * W/nf * 0.29'" 
pd="'2*int((nf+1)/2) * (W/nf + 0.29)'"
as="'int((nf+2)/2) * W/nf * 0.29'" 
ps="'2*int((nf+2)/2) * (W/nf + 0.29)'"
nrd="'0.29 / W'" nrs="'0.29 / W'"
sa=0 sb=0 sd=0
model=pfet_01v8
spiceprefix=X
}
C {sky130_fd_pr/pfet_01v8.sym} 150 940 0 0 {name=M105
L=0.5
W=1
nf=1
mult=1
ad="'int((nf+1)/2) * W/nf * 0.29'" 
pd="'2*int((nf+1)/2) * (W/nf + 0.29)'"
as="'int((nf+2)/2) * W/nf * 0.29'" 
ps="'2*int((nf+2)/2) * (W/nf + 0.29)'"
nrd="'0.29 / W'" nrs="'0.29 / W'"
sa=0 sb=0 sd=0
model=pfet_01v8
spiceprefix=X
}
C {devices/lab_wire.sym} 100 890 0 0 {name=p114 sig_type=std_logic lab=Vdd
}
C {devices/lab_pin.sym} -225 940 0 0 {name=p115 sig_type=std_logic lab=Vo2-
}
C {devices/lab_pin.sym} 405 940 0 1 {name=p116 sig_type=std_logic lab=Vo2+
}
C {sky130_fd_pr/pfet_01v8.sym} 20 1110 0 1 {name=M106
L=0.5
W=1
nf=1
mult=1
ad="'int((nf+1)/2) * W/nf * 0.29'" 
pd="'2*int((nf+1)/2) * (W/nf + 0.29)'"
as="'int((nf+2)/2) * W/nf * 0.29'" 
ps="'2*int((nf+2)/2) * (W/nf + 0.29)'"
nrd="'0.29 / W'" nrs="'0.29 / W'"
sa=0 sb=0 sd=0
model=pfet_01v8
spiceprefix=X
}
C {sky130_fd_pr/pfet_01v8.sym} 150 1110 0 0 {name=M107
L=0.5
W=1
nf=1
mult=1
ad="'int((nf+1)/2) * W/nf * 0.29'" 
pd="'2*int((nf+1)/2) * (W/nf + 0.29)'"
as="'int((nf+2)/2) * W/nf * 0.29'" 
ps="'2*int((nf+2)/2) * (W/nf + 0.29)'"
nrd="'0.29 / W'" nrs="'0.29 / W'"
sa=0 sb=0 sd=0
model=pfet_01v8
spiceprefix=X
}
C {sky130_fd_pr/nfet_01v8.sym} 20 1290 0 1 {name=M108
L=0.5
W=1
nf=1 
mult=1
ad="'int((nf+1)/2) * W/nf * 0.29'" 
pd="'2*int((nf+1)/2) * (W/nf + 0.29)'"
as="'int((nf+2)/2) * W/nf * 0.29'" 
ps="'2*int((nf+2)/2) * (W/nf + 0.29)'"
nrd="'0.29 / W'" nrs="'0.29 / W'"
sa=0 sb=0 sd=0
model=nfet_01v8
spiceprefix=X
}
C {sky130_fd_pr/nfet_01v8.sym} 150 1290 0 0 {name=M109
L=0.5
W=1
nf=1 
mult=1
ad="'int((nf+1)/2) * W/nf * 0.29'" 
pd="'2*int((nf+1)/2) * (W/nf + 0.29)'"
as="'int((nf+2)/2) * W/nf * 0.29'" 
ps="'2*int((nf+2)/2) * (W/nf + 0.29)'"
nrd="'0.29 / W'" nrs="'0.29 / W'"
sa=0 sb=0 sd=0
model=nfet_01v8
spiceprefix=X
}
C {sky130_fd_pr/nfet_01v8.sym} -20 1400 0 0 {name=M110
L=0.5
W=1
nf=1 
mult=1
ad="'int((nf+1)/2) * W/nf * 0.29'" 
pd="'2*int((nf+1)/2) * (W/nf + 0.29)'"
as="'int((nf+2)/2) * W/nf * 0.29'" 
ps="'2*int((nf+2)/2) * (W/nf + 0.29)'"
nrd="'0.29 / W'" nrs="'0.29 / W'"
sa=0 sb=0 sd=0
model=nfet_01v8
spiceprefix=X
}
C {sky130_fd_pr/nfet_01v8.sym} -170 1400 0 0 {name=M111
L=0.5
W=1
nf=1 
mult=1
ad="'int((nf+1)/2) * W/nf * 0.29'" 
pd="'2*int((nf+1)/2) * (W/nf + 0.29)'"
as="'int((nf+2)/2) * W/nf * 0.29'" 
ps="'2*int((nf+2)/2) * (W/nf + 0.29)'"
nrd="'0.29 / W'" nrs="'0.29 / W'"
sa=0 sb=0 sd=0
model=nfet_01v8
spiceprefix=X
}
C {sky130_fd_pr/nfet_01v8.sym} 350 1400 0 1 {name=M112
L=0.5
W=1
nf=1 
mult=1
ad="'int((nf+1)/2) * W/nf * 0.29'" 
pd="'2*int((nf+1)/2) * (W/nf + 0.29)'"
as="'int((nf+2)/2) * W/nf * 0.29'" 
ps="'2*int((nf+2)/2) * (W/nf + 0.29)'"
nrd="'0.29 / W'" nrs="'0.29 / W'"
sa=0 sb=0 sd=0
model=nfet_01v8
spiceprefix=X
}
C {sky130_fd_pr/nfet_01v8.sym} 190 1400 0 1 {name=M113
L=0.5
W=1
nf=1 
mult=1
ad="'int((nf+1)/2) * W/nf * 0.29'" 
pd="'2*int((nf+1)/2) * (W/nf + 0.29)'"
as="'int((nf+2)/2) * W/nf * 0.29'" 
ps="'2*int((nf+2)/2) * (W/nf + 0.29)'"
nrd="'0.29 / W'" nrs="'0.29 / W'"
sa=0 sb=0 sd=0
model=nfet_01v8
spiceprefix=X
lab=Vo2+}
C {devices/lab_wire.sym} -50 1400 0 0 {name=p117 sig_type=std_logic lab=Vo2-
}
C {devices/lab_wire.sym} 230 1400 0 0 {name=p118 sig_type=std_logic lab=Vo2+

}
C {devices/lab_wire.sym} -640 1550 0 0 {name=p119 sig_type=std_logic lab=Vo2+
}
C {devices/lab_wire.sym} -620 1790 0 0 {name=p120 sig_type=std_logic lab=Vo2-
}
C {devices/lab_wire.sym} -420 1570 0 0 {name=p121 sig_type=std_logic lab=Vo3+
}
C {devices/lab_wire.sym} -480 1810 0 0 {name=p122 sig_type=std_logic lab=Vo3-
}
C {devices/lab_wire.sym} 50 940 0 1 {name=p123 sig_type=std_logic lab=Vo3+
}
C {devices/lab_wire.sym} 120 940 0 0 {name=p124 sig_type=std_logic lab=Vo3-
}
C {devices/lab_wire.sym} -210 1400 0 0 {name=p125 sig_type=std_logic lab=Vo3+
}
C {devices/lab_wire.sym} 380 1400 0 1 {name=p126 sig_type=std_logic lab=Vo3-
}
C {devices/lab_wire.sym} 50 1210 0 0 {name=p127 sig_type=std_logic lab=Q2
}
C {devices/lab_wire.sym} 120 1240 0 0 {name=p128 sig_type=std_logic lab=Q3
}
C {devices/lab_wire.sym} -540 1470 0 0 {name=p129 sig_type=std_logic lab=Vdd
}
C {sky130_fd_pr/pfet_01v8.sym} -560 1530 0 0 {name=M114
L=0.5
W=1
nf=1
mult=1
ad="'int((nf+1)/2) * W/nf * 0.29'" 
pd="'2*int((nf+1)/2) * (W/nf + 0.29)'"
as="'int((nf+2)/2) * W/nf * 0.29'" 
ps="'2*int((nf+2)/2) * (W/nf + 0.29)'"
nrd="'0.29 / W'" nrs="'0.29 / W'"
sa=0 sb=0 sd=0
model=pfet_01v8
spiceprefix=X
}
C {sky130_fd_pr/nfet_01v8.sym} -560 1610 0 0 {name=M115
L=0.5
W=1
nf=1 
mult=1
ad="'int((nf+1)/2) * W/nf * 0.29'" 
pd="'2*int((nf+1)/2) * (W/nf + 0.29)'"
as="'int((nf+2)/2) * W/nf * 0.29'" 
ps="'2*int((nf+2)/2) * (W/nf + 0.29)'"
nrd="'0.29 / W'" nrs="'0.29 / W'"
sa=0 sb=0 sd=0
model=nfet_01v8
spiceprefix=X
}
C {sky130_fd_pr/pfet_01v8.sym} -560 1770 0 0 {name=M116
L=0.5
W=1
nf=1
mult=1
ad="'int((nf+1)/2) * W/nf * 0.29'" 
pd="'2*int((nf+1)/2) * (W/nf + 0.29)'"
as="'int((nf+2)/2) * W/nf * 0.29'" 
ps="'2*int((nf+2)/2) * (W/nf + 0.29)'"
nrd="'0.29 / W'" nrs="'0.29 / W'"
sa=0 sb=0 sd=0
model=pfet_01v8
spiceprefix=X
}
C {sky130_fd_pr/nfet_01v8.sym} -560 1850 0 0 {name=M117
L=0.5
W=1
nf=1 
mult=1
ad="'int((nf+1)/2) * W/nf * 0.29'" 
pd="'2*int((nf+1)/2) * (W/nf + 0.29)'"
as="'int((nf+2)/2) * W/nf * 0.29'" 
ps="'2*int((nf+2)/2) * (W/nf + 0.29)'"
nrd="'0.29 / W'" nrs="'0.29 / W'"
sa=0 sb=0 sd=0
model=nfet_01v8
spiceprefix=X
}
C {devices/lab_wire.sym} -540 1720 0 0 {name=p130 sig_type=std_logic lab=Vdd
}
C {devices/lab_wire.sym} -420 1240 0 0 {name=p131 sig_type=std_logic lab=Vc-
}
C {devices/lab_wire.sym} -1010 1240 0 0 {name=p132 sig_type=std_logic lab=Vc+
}
C {devices/lab_pin.sym} -1330 200 1 0 {name=p133 sig_type=std_logic lab=Vdd}
C {sky130_fd_pr/pfet_01v8_lvt.sym} -1360 270 0 0 {name=M118
L=4
W=1
nf=1
mult=1
ad="'int((nf+1)/2) * W/nf * 0.29'" 
pd="'2*int((nf+1)/2) * (W/nf + 0.29)'"
as="'int((nf+2)/2) * W/nf * 0.29'" 
ps="'2*int((nf+2)/2) * (W/nf + 0.29)'"
nrd="'0.29 / W'" nrs="'0.29 / W'"
sa=0 sb=0 sd=0
model=pfet_01v8_lvt
spiceprefix=X
}
C {sky130_fd_pr/pfet_01v8_lvt.sym} -1360 380 0 0 {name=M119
L=0.5
W=1
nf=1
mult=1
ad="'int((nf+1)/2) * W/nf * 0.29'" 
pd="'2*int((nf+1)/2) * (W/nf + 0.29)'"
as="'int((nf+2)/2) * W/nf * 0.29'" 
ps="'2*int((nf+2)/2) * (W/nf + 0.29)'"
nrd="'0.29 / W'" nrs="'0.29 / W'"
sa=0 sb=0 sd=0
model=pfet_01v8_lvt
spiceprefix=X
}
C {sky130_fd_pr/pfet_01v8_lvt.sym} -1360 480 0 0 {name=M120
L=4
W=1
nf=1
mult=1
ad="'int((nf+1)/2) * W/nf * 0.29'" 
pd="'2*int((nf+1)/2) * (W/nf + 0.29)'"
as="'int((nf+2)/2) * W/nf * 0.29'" 
ps="'2*int((nf+2)/2) * (W/nf + 0.29)'"
nrd="'0.29 / W'" nrs="'0.29 / W'"
sa=0 sb=0 sd=0
model=pfet_01v8_lvt
spiceprefix=X
}
C {devices/lab_pin.sym} -1340 540 2 0 {name=p134 sig_type=std_logic lab=gnd}
C {devices/lab_wire.sym} -1270 440 0 0 {name=p135 sig_type=std_logic lab=Vc-
}
C {devices/lab_wire.sym} -1280 340 0 0 {name=p136 sig_type=std_logic lab=Vc+
}
C {sky130_fd_pr/nfet_01v8.sym} -1350 1080 0 0 {name=M121
L=0.15
W=20.16
nf=1 
mult=1
ad="'int((nf+1)/2) * W/nf * 0.29'" 
pd="'2*int((nf+1)/2) * (W/nf + 0.29)'"
as="'int((nf+2)/2) * W/nf * 0.29'" 
ps="'2*int((nf+2)/2) * (W/nf + 0.29)'"
nrd="'0.29 / W'" nrs="'0.29 / W'"
sa=0 sb=0 sd=0
model=nfet_01v8
spiceprefix=X
}
C {devices/lab_wire.sym} -1390 1080 0 0 {name=p137 sig_type=std_logic lab=Vdd
}
C {devices/iopin.sym} -1390 -240 0 0 {name=p183 lab=gnd}
C {devices/iopin.sym} -1390 -270 0 0 {name=p184 lab=Vdd}
C {devices/ipin.sym} -1330 -110 0 0 {name=p3 lab=vo1}
C {devices/ipin.sym} -1320 -70 0 0 {name=p4 lab=vo2}
C {devices/ipin.sym} -1310 -30 0 0 {name=p5 lab=Vc-}
C {devices/ipin.sym} -1310 10 0 0 {name=p8 lab=vc+}
C {devices/ipin.sym} -1330 50 0 0 {name=p9 lab=clk}
C {devices/opin.sym} -1370 80 0 0 {name=p12 lab=Q}
C {devices/opin.sym} -1310 120 0 0 {name=p1 lab=Q2}
C {devices/lab_wire.sym} -720 240 0 0 {name=p2 sig_type=std_logic lab=gnd
}
C {devices/lab_wire.sym} 90 300 0 0 {name=p6 sig_type=std_logic lab=gnd
}
C {devices/lab_pin.sym} -560 460 2 0 {name=p7 sig_type=std_logic lab=gnd}
C {devices/lab_pin.sym} -560 700 2 0 {name=p10 sig_type=std_logic lab=gnd}
C {devices/lab_pin.sym} 30 200 2 0 {name=p11 sig_type=std_logic lab=gnd}
C {devices/lab_wire.sym} -730 40 0 0 {name=p13 sig_type=std_logic lab=gnd
}
C {devices/lab_wire.sym} -520 40 0 0 {name=p14 sig_type=std_logic lab=gnd
}
C {devices/lab_wire.sym} -930 40 0 0 {name=p15 sig_type=std_logic lab=gnd
}
C {devices/lab_wire.sym} -900 -90 0 0 {name=p16 sig_type=std_logic lab=gnd
}
C {devices/lab_wire.sym} -580 -90 0 0 {name=p17 sig_type=std_logic lab=gnd
}
C {devices/lab_pin.sym} -700 1440 2 0 {name=p18 sig_type=std_logic lab=gnd}
C {devices/lab_pin.sym} -920 1240 2 0 {name=p19 sig_type=std_logic lab=gnd}
C {devices/lab_pin.sym} -500 1240 2 1 {name=p20 sig_type=std_logic lab=gnd}
C {devices/lab_pin.sym} -720 1240 1 1 {name=p21 sig_type=std_logic lab=gnd}
C {devices/lab_pin.sym} -560 1110 1 1 {name=p22 sig_type=std_logic lab=gnd}
C {devices/lab_pin.sym} -880 1110 1 1 {name=p23 sig_type=std_logic lab=gnd}
C {devices/lab_pin.sym} -540 1660 1 1 {name=p24 sig_type=std_logic lab=gnd}
C {devices/lab_pin.sym} -540 1900 1 1 {name=p25 sig_type=std_logic lab=gnd}
C {devices/lab_pin.sym} 110 1500 1 1 {name=p26 sig_type=std_logic lab=gnd}
C {devices/lab_pin.sym} 240 1290 1 1 {name=p27 sig_type=std_logic lab=gnd}
